VERSION 5.7 ;
  NOWIREEXTENSIONATPIN ON ;
  DIVIDERCHAR "/" ;
  BUSBITCHARS "[]" ;
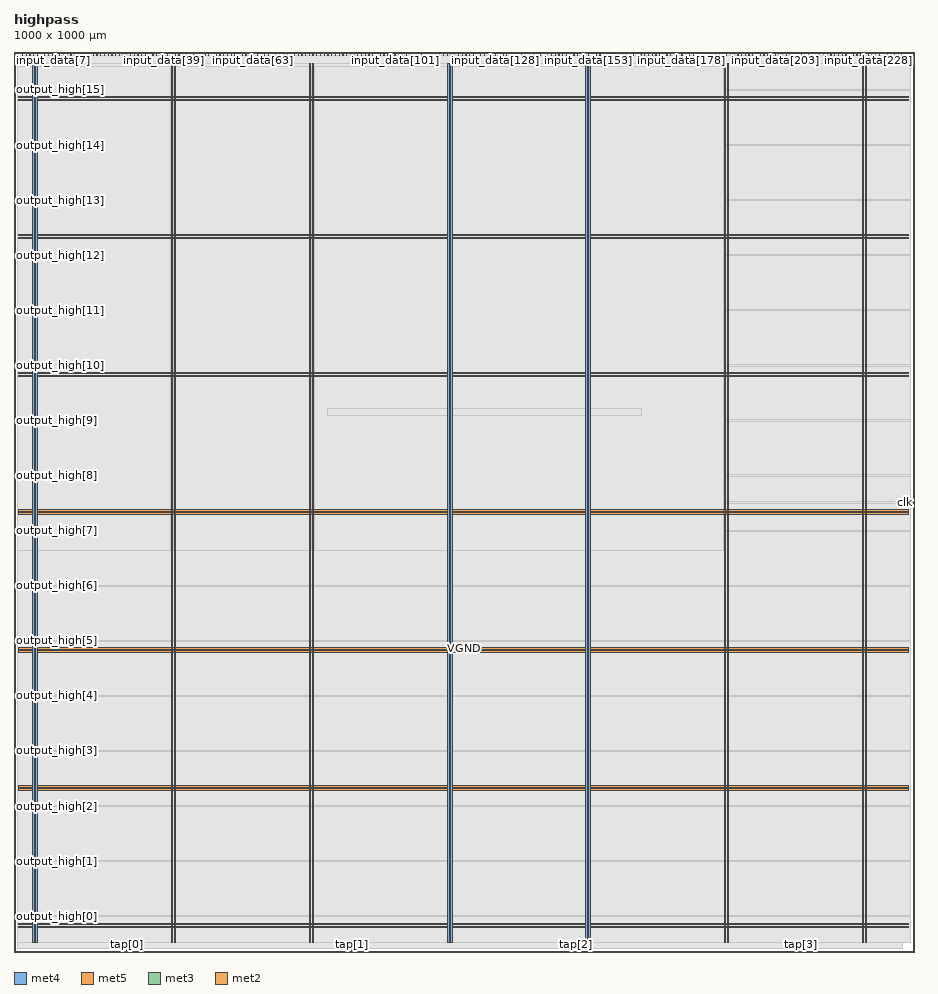
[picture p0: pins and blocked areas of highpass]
MACRO highpass
  CLASS BLOCK ;
  FOREIGN highpass ;
  ORIGIN 0.000 0.000 ;
  SIZE 1000.000 BY 1000.000 ;
  PIN VGND
    DIRECTION INOUT ;
    USE GROUND ;
    PORT
      LAYER met4 ;
        RECT 24.340 10.640 25.940 987.600 ;
    END
    PORT
      LAYER met4 ;
        RECT 177.940 10.640 179.540 987.600 ;
    END
    PORT
      LAYER met4 ;
        RECT 331.540 10.640 333.140 987.600 ;
    END
    PORT
      LAYER met4 ;
        RECT 485.140 10.640 486.740 987.600 ;
    END
    PORT
      LAYER met4 ;
        RECT 638.740 10.640 640.340 987.600 ;
    END
    PORT
      LAYER met4 ;
        RECT 792.340 10.640 793.940 987.600 ;
    END
    PORT
      LAYER met4 ;
        RECT 945.940 10.640 947.540 987.600 ;
    END
    PORT
      LAYER met5 ;
        RECT 5.280 30.030 994.300 31.630 ;
    END
    PORT
      LAYER met5 ;
        RECT 5.280 183.210 994.300 184.810 ;
    END
    PORT
      LAYER met5 ;
        RECT 5.280 336.390 994.300 337.990 ;
    END
    PORT
      LAYER met5 ;
        RECT 5.280 489.570 994.300 491.170 ;
    END
    PORT
      LAYER met5 ;
        RECT 5.280 642.750 994.300 644.350 ;
    END
    PORT
      LAYER met5 ;
        RECT 5.280 795.930 994.300 797.530 ;
    END
    PORT
      LAYER met5 ;
        RECT 5.280 949.110 994.300 950.710 ;
    END
  END VGND
  PIN VPWR
    DIRECTION INOUT ;
    USE POWER ;
    PORT
      LAYER met4 ;
        RECT 21.040 10.640 22.640 987.600 ;
    END
    PORT
      LAYER met4 ;
        RECT 174.640 10.640 176.240 987.600 ;
    END
    PORT
      LAYER met4 ;
        RECT 328.240 10.640 329.840 987.600 ;
    END
    PORT
      LAYER met4 ;
        RECT 481.840 10.640 483.440 987.600 ;
    END
    PORT
      LAYER met4 ;
        RECT 635.440 10.640 637.040 987.600 ;
    END
    PORT
      LAYER met4 ;
        RECT 789.040 10.640 790.640 987.600 ;
    END
    PORT
      LAYER met4 ;
        RECT 942.640 10.640 944.240 987.600 ;
    END
    PORT
      LAYER met5 ;
        RECT 5.280 26.730 994.300 28.330 ;
    END
    PORT
      LAYER met5 ;
        RECT 5.280 179.910 994.300 181.510 ;
    END
    PORT
      LAYER met5 ;
        RECT 5.280 333.090 994.300 334.690 ;
    END
    PORT
      LAYER met5 ;
        RECT 5.280 486.270 994.300 487.870 ;
    END
    PORT
      LAYER met5 ;
        RECT 5.280 639.450 994.300 641.050 ;
    END
    PORT
      LAYER met5 ;
        RECT 5.280 792.630 994.300 794.230 ;
    END
    PORT
      LAYER met5 ;
        RECT 5.280 945.810 994.300 947.410 ;
    END
  END VPWR
  PIN clk
    DIRECTION INPUT ;
    USE SIGNAL ;
    ANTENNAGATEAREA 0.852000 ;
    PORT
      LAYER met3 ;
        RECT 996.000 499.160 1000.000 499.760 ;
    END
  END clk
  PIN input_data[0]
    DIRECTION INPUT ;
    USE SIGNAL ;
    ANTENNAGATEAREA 0.159000 ;
    PORT
      LAYER met2 ;
        RECT 5.150 996.000 5.430 1000.000 ;
    END
  END input_data[0]
  PIN input_data[100]
    DIRECTION INPUT ;
    USE SIGNAL ;
    ANTENNAGATEAREA 0.213000 ;
    PORT
      LAYER met2 ;
        RECT 419.150 996.000 419.430 1000.000 ;
    END
  END input_data[100]
  PIN input_data[101]
    DIRECTION INPUT ;
    USE SIGNAL ;
    ANTENNAGATEAREA 0.196500 ;
    PORT
      LAYER met2 ;
        RECT 423.290 996.000 423.570 1000.000 ;
    END
  END input_data[101]
  PIN input_data[102]
    DIRECTION INPUT ;
    USE SIGNAL ;
    ANTENNAGATEAREA 0.196500 ;
    PORT
      LAYER met2 ;
        RECT 427.430 996.000 427.710 1000.000 ;
    END
  END input_data[102]
  PIN input_data[103]
    DIRECTION INPUT ;
    USE SIGNAL ;
    ANTENNAGATEAREA 0.196500 ;
    PORT
      LAYER met2 ;
        RECT 431.570 996.000 431.850 1000.000 ;
    END
  END input_data[103]
  PIN input_data[104]
    DIRECTION INPUT ;
    USE SIGNAL ;
    ANTENNAGATEAREA 0.196500 ;
    PORT
      LAYER met2 ;
        RECT 435.710 996.000 435.990 1000.000 ;
    END
  END input_data[104]
  PIN input_data[105]
    DIRECTION INPUT ;
    USE SIGNAL ;
    ANTENNAGATEAREA 0.196500 ;
    PORT
      LAYER met2 ;
        RECT 439.850 996.000 440.130 1000.000 ;
    END
  END input_data[105]
  PIN input_data[106]
    DIRECTION INPUT ;
    USE SIGNAL ;
    ANTENNAGATEAREA 0.196500 ;
    PORT
      LAYER met2 ;
        RECT 443.990 996.000 444.270 1000.000 ;
    END
  END input_data[106]
  PIN input_data[107]
    DIRECTION INPUT ;
    USE SIGNAL ;
    ANTENNAGATEAREA 0.196500 ;
    PORT
      LAYER met2 ;
        RECT 448.130 996.000 448.410 1000.000 ;
    END
  END input_data[107]
  PIN input_data[108]
    DIRECTION INPUT ;
    USE SIGNAL ;
    ANTENNAGATEAREA 0.213000 ;
    PORT
      LAYER met2 ;
        RECT 452.270 996.000 452.550 1000.000 ;
    END
  END input_data[108]
  PIN input_data[109]
    DIRECTION INPUT ;
    USE SIGNAL ;
    ANTENNAGATEAREA 0.196500 ;
    PORT
      LAYER met2 ;
        RECT 456.410 996.000 456.690 1000.000 ;
    END
  END input_data[109]
  PIN input_data[10]
    DIRECTION INPUT ;
    USE SIGNAL ;
    ANTENNAGATEAREA 0.495000 ;
    PORT
      LAYER met2 ;
        RECT 46.550 996.000 46.830 1000.000 ;
    END
  END input_data[10]
  PIN input_data[110]
    DIRECTION INPUT ;
    USE SIGNAL ;
    ANTENNAGATEAREA 0.196500 ;
    PORT
      LAYER met2 ;
        RECT 460.550 996.000 460.830 1000.000 ;
    END
  END input_data[110]
  PIN input_data[111]
    DIRECTION INPUT ;
    USE SIGNAL ;
    ANTENNAGATEAREA 0.196500 ;
    PORT
      LAYER met2 ;
        RECT 464.690 996.000 464.970 1000.000 ;
    END
  END input_data[111]
  PIN input_data[112]
    DIRECTION INPUT ;
    USE SIGNAL ;
    ANTENNAGATEAREA 0.159000 ;
    PORT
      LAYER met2 ;
        RECT 468.830 996.000 469.110 1000.000 ;
    END
  END input_data[112]
  PIN input_data[113]
    DIRECTION INPUT ;
    USE SIGNAL ;
    ANTENNAGATEAREA 0.213000 ;
    PORT
      LAYER met2 ;
        RECT 472.970 996.000 473.250 1000.000 ;
    END
  END input_data[113]
  PIN input_data[114]
    DIRECTION INPUT ;
    USE SIGNAL ;
    ANTENNAGATEAREA 0.213000 ;
    PORT
      LAYER met2 ;
        RECT 477.110 996.000 477.390 1000.000 ;
    END
  END input_data[114]
  PIN input_data[115]
    DIRECTION INPUT ;
    USE SIGNAL ;
    ANTENNAGATEAREA 0.213000 ;
    PORT
      LAYER met2 ;
        RECT 481.250 996.000 481.530 1000.000 ;
    END
  END input_data[115]
  PIN input_data[116]
    DIRECTION INPUT ;
    USE SIGNAL ;
    ANTENNAGATEAREA 0.159000 ;
    PORT
      LAYER met2 ;
        RECT 485.390 996.000 485.670 1000.000 ;
    END
  END input_data[116]
  PIN input_data[117]
    DIRECTION INPUT ;
    USE SIGNAL ;
    ANTENNAGATEAREA 0.213000 ;
    PORT
      LAYER met2 ;
        RECT 489.530 996.000 489.810 1000.000 ;
    END
  END input_data[117]
  PIN input_data[118]
    DIRECTION INPUT ;
    USE SIGNAL ;
    ANTENNAGATEAREA 0.213000 ;
    PORT
      LAYER met2 ;
        RECT 493.670 996.000 493.950 1000.000 ;
    END
  END input_data[118]
  PIN input_data[119]
    DIRECTION INPUT ;
    USE SIGNAL ;
    ANTENNAGATEAREA 0.196500 ;
    PORT
      LAYER met2 ;
        RECT 497.810 996.000 498.090 1000.000 ;
    END
  END input_data[119]
  PIN input_data[11]
    DIRECTION INPUT ;
    USE SIGNAL ;
    ANTENNAGATEAREA 0.426000 ;
    PORT
      LAYER met2 ;
        RECT 50.690 996.000 50.970 1000.000 ;
    END
  END input_data[11]
  PIN input_data[120]
    DIRECTION INPUT ;
    USE SIGNAL ;
    ANTENNAGATEAREA 0.213000 ;
    PORT
      LAYER met2 ;
        RECT 501.950 996.000 502.230 1000.000 ;
    END
  END input_data[120]
  PIN input_data[121]
    DIRECTION INPUT ;
    USE SIGNAL ;
    ANTENNAGATEAREA 0.159000 ;
    PORT
      LAYER met2 ;
        RECT 506.090 996.000 506.370 1000.000 ;
    END
  END input_data[121]
  PIN input_data[122]
    DIRECTION INPUT ;
    USE SIGNAL ;
    ANTENNAGATEAREA 0.213000 ;
    PORT
      LAYER met2 ;
        RECT 510.230 996.000 510.510 1000.000 ;
    END
  END input_data[122]
  PIN input_data[123]
    DIRECTION INPUT ;
    USE SIGNAL ;
    ANTENNAGATEAREA 0.213000 ;
    PORT
      LAYER met2 ;
        RECT 514.370 996.000 514.650 1000.000 ;
    END
  END input_data[123]
  PIN input_data[124]
    DIRECTION INPUT ;
    USE SIGNAL ;
    ANTENNAGATEAREA 0.159000 ;
    PORT
      LAYER met2 ;
        RECT 518.510 996.000 518.790 1000.000 ;
    END
  END input_data[124]
  PIN input_data[125]
    DIRECTION INPUT ;
    USE SIGNAL ;
    ANTENNAGATEAREA 0.196500 ;
    PORT
      LAYER met2 ;
        RECT 522.650 996.000 522.930 1000.000 ;
    END
  END input_data[125]
  PIN input_data[126]
    DIRECTION INPUT ;
    USE SIGNAL ;
    ANTENNAGATEAREA 0.196500 ;
    PORT
      LAYER met2 ;
        RECT 526.790 996.000 527.070 1000.000 ;
    END
  END input_data[126]
  PIN input_data[127]
    DIRECTION INPUT ;
    USE SIGNAL ;
    PORT
      LAYER met2 ;
        RECT 530.930 996.000 531.210 1000.000 ;
    END
  END input_data[127]
  PIN input_data[128]
    DIRECTION INPUT ;
    USE SIGNAL ;
    ANTENNAGATEAREA 0.159000 ;
    PORT
      LAYER met2 ;
        RECT 535.070 996.000 535.350 1000.000 ;
    END
  END input_data[128]
  PIN input_data[129]
    DIRECTION INPUT ;
    USE SIGNAL ;
    ANTENNAGATEAREA 0.159000 ;
    PORT
      LAYER met2 ;
        RECT 539.210 996.000 539.490 1000.000 ;
    END
  END input_data[129]
  PIN input_data[12]
    DIRECTION INPUT ;
    USE SIGNAL ;
    ANTENNAGATEAREA 0.742500 ;
    PORT
      LAYER met2 ;
        RECT 54.830 996.000 55.110 1000.000 ;
    END
  END input_data[12]
  PIN input_data[130]
    DIRECTION INPUT ;
    USE SIGNAL ;
    ANTENNAGATEAREA 0.213000 ;
    PORT
      LAYER met2 ;
        RECT 543.350 996.000 543.630 1000.000 ;
    END
  END input_data[130]
  PIN input_data[131]
    DIRECTION INPUT ;
    USE SIGNAL ;
    ANTENNAGATEAREA 0.213000 ;
    PORT
      LAYER met2 ;
        RECT 547.490 996.000 547.770 1000.000 ;
    END
  END input_data[131]
  PIN input_data[132]
    DIRECTION INPUT ;
    USE SIGNAL ;
    ANTENNAGATEAREA 0.213000 ;
    PORT
      LAYER met2 ;
        RECT 551.630 996.000 551.910 1000.000 ;
    END
  END input_data[132]
  PIN input_data[133]
    DIRECTION INPUT ;
    USE SIGNAL ;
    ANTENNAGATEAREA 0.426000 ;
    PORT
      LAYER met2 ;
        RECT 555.770 996.000 556.050 1000.000 ;
    END
  END input_data[133]
  PIN input_data[134]
    DIRECTION INPUT ;
    USE SIGNAL ;
    ANTENNAGATEAREA 0.247500 ;
    PORT
      LAYER met2 ;
        RECT 559.910 996.000 560.190 1000.000 ;
    END
  END input_data[134]
  PIN input_data[135]
    DIRECTION INPUT ;
    USE SIGNAL ;
    ANTENNAGATEAREA 0.426000 ;
    PORT
      LAYER met2 ;
        RECT 564.050 996.000 564.330 1000.000 ;
    END
  END input_data[135]
  PIN input_data[136]
    DIRECTION INPUT ;
    USE SIGNAL ;
    ANTENNAGATEAREA 0.852000 ;
    PORT
      LAYER met2 ;
        RECT 568.190 996.000 568.470 1000.000 ;
    END
  END input_data[136]
  PIN input_data[137]
    DIRECTION INPUT ;
    USE SIGNAL ;
    ANTENNAGATEAREA 0.742500 ;
    PORT
      LAYER met2 ;
        RECT 572.330 996.000 572.610 1000.000 ;
    END
  END input_data[137]
  PIN input_data[138]
    DIRECTION INPUT ;
    USE SIGNAL ;
    ANTENNAGATEAREA 0.426000 ;
    PORT
      LAYER met2 ;
        RECT 576.470 996.000 576.750 1000.000 ;
    END
  END input_data[138]
  PIN input_data[139]
    DIRECTION INPUT ;
    USE SIGNAL ;
    ANTENNAGATEAREA 0.495000 ;
    PORT
      LAYER met2 ;
        RECT 580.610 996.000 580.890 1000.000 ;
    END
  END input_data[139]
  PIN input_data[13]
    DIRECTION INPUT ;
    USE SIGNAL ;
    ANTENNAGATEAREA 0.742500 ;
    PORT
      LAYER met2 ;
        RECT 58.970 996.000 59.250 1000.000 ;
    END
  END input_data[13]
  PIN input_data[140]
    DIRECTION INPUT ;
    USE SIGNAL ;
    ANTENNAGATEAREA 0.426000 ;
    PORT
      LAYER met2 ;
        RECT 584.750 996.000 585.030 1000.000 ;
    END
  END input_data[140]
  PIN input_data[141]
    DIRECTION INPUT ;
    USE SIGNAL ;
    ANTENNAGATEAREA 0.426000 ;
    PORT
      LAYER met2 ;
        RECT 588.890 996.000 589.170 1000.000 ;
    END
  END input_data[141]
  PIN input_data[142]
    DIRECTION INPUT ;
    USE SIGNAL ;
    ANTENNAGATEAREA 0.213000 ;
    PORT
      LAYER met2 ;
        RECT 593.030 996.000 593.310 1000.000 ;
    END
  END input_data[142]
  PIN input_data[143]
    DIRECTION INPUT ;
    USE SIGNAL ;
    ANTENNAGATEAREA 0.159000 ;
    PORT
      LAYER met2 ;
        RECT 597.170 996.000 597.450 1000.000 ;
    END
  END input_data[143]
  PIN input_data[144]
    DIRECTION INPUT ;
    USE SIGNAL ;
    ANTENNAGATEAREA 0.213000 ;
    PORT
      LAYER met2 ;
        RECT 601.310 996.000 601.590 1000.000 ;
    END
  END input_data[144]
  PIN input_data[145]
    DIRECTION INPUT ;
    USE SIGNAL ;
    ANTENNAGATEAREA 0.159000 ;
    PORT
      LAYER met2 ;
        RECT 605.450 996.000 605.730 1000.000 ;
    END
  END input_data[145]
  PIN input_data[146]
    DIRECTION INPUT ;
    USE SIGNAL ;
    ANTENNAGATEAREA 0.159000 ;
    PORT
      LAYER met2 ;
        RECT 609.590 996.000 609.870 1000.000 ;
    END
  END input_data[146]
  PIN input_data[147]
    DIRECTION INPUT ;
    USE SIGNAL ;
    ANTENNAGATEAREA 0.159000 ;
    PORT
      LAYER met2 ;
        RECT 613.730 996.000 614.010 1000.000 ;
    END
  END input_data[147]
  PIN input_data[148]
    DIRECTION INPUT ;
    USE SIGNAL ;
    ANTENNAGATEAREA 0.159000 ;
    PORT
      LAYER met2 ;
        RECT 617.870 996.000 618.150 1000.000 ;
    END
  END input_data[148]
  PIN input_data[149]
    DIRECTION INPUT ;
    USE SIGNAL ;
    ANTENNAGATEAREA 0.213000 ;
    PORT
      LAYER met2 ;
        RECT 622.010 996.000 622.290 1000.000 ;
    END
  END input_data[149]
  PIN input_data[14]
    DIRECTION INPUT ;
    USE SIGNAL ;
    ANTENNAGATEAREA 0.213000 ;
    PORT
      LAYER met2 ;
        RECT 63.110 996.000 63.390 1000.000 ;
    END
  END input_data[14]
  PIN input_data[150]
    DIRECTION INPUT ;
    USE SIGNAL ;
    ANTENNAGATEAREA 0.159000 ;
    PORT
      LAYER met2 ;
        RECT 626.150 996.000 626.430 1000.000 ;
    END
  END input_data[150]
  PIN input_data[151]
    DIRECTION INPUT ;
    USE SIGNAL ;
    ANTENNAGATEAREA 0.213000 ;
    PORT
      LAYER met2 ;
        RECT 630.290 996.000 630.570 1000.000 ;
    END
  END input_data[151]
  PIN input_data[152]
    DIRECTION INPUT ;
    USE SIGNAL ;
    ANTENNAGATEAREA 0.213000 ;
    PORT
      LAYER met2 ;
        RECT 634.430 996.000 634.710 1000.000 ;
    END
  END input_data[152]
  PIN input_data[153]
    DIRECTION INPUT ;
    USE SIGNAL ;
    ANTENNAGATEAREA 0.159000 ;
    PORT
      LAYER met2 ;
        RECT 638.570 996.000 638.850 1000.000 ;
    END
  END input_data[153]
  PIN input_data[154]
    DIRECTION INPUT ;
    USE SIGNAL ;
    ANTENNAGATEAREA 0.159000 ;
    PORT
      LAYER met2 ;
        RECT 642.710 996.000 642.990 1000.000 ;
    END
  END input_data[154]
  PIN input_data[155]
    DIRECTION INPUT ;
    USE SIGNAL ;
    ANTENNAGATEAREA 0.159000 ;
    PORT
      LAYER met2 ;
        RECT 646.850 996.000 647.130 1000.000 ;
    END
  END input_data[155]
  PIN input_data[156]
    DIRECTION INPUT ;
    USE SIGNAL ;
    ANTENNAGATEAREA 0.742500 ;
    PORT
      LAYER met2 ;
        RECT 650.990 996.000 651.270 1000.000 ;
    END
  END input_data[156]
  PIN input_data[157]
    DIRECTION INPUT ;
    USE SIGNAL ;
    ANTENNAGATEAREA 0.247500 ;
    PORT
      LAYER met2 ;
        RECT 655.130 996.000 655.410 1000.000 ;
    END
  END input_data[157]
  PIN input_data[158]
    DIRECTION INPUT ;
    USE SIGNAL ;
    ANTENNAGATEAREA 0.196500 ;
    PORT
      LAYER met2 ;
        RECT 659.270 996.000 659.550 1000.000 ;
    END
  END input_data[158]
  PIN input_data[159]
    DIRECTION INPUT ;
    USE SIGNAL ;
    ANTENNAGATEAREA 0.213000 ;
    PORT
      LAYER met2 ;
        RECT 663.410 996.000 663.690 1000.000 ;
    END
  END input_data[159]
  PIN input_data[15]
    DIRECTION INPUT ;
    USE SIGNAL ;
    ANTENNAGATEAREA 0.213000 ;
    PORT
      LAYER met2 ;
        RECT 67.250 996.000 67.530 1000.000 ;
    END
  END input_data[15]
  PIN input_data[160]
    DIRECTION INPUT ;
    USE SIGNAL ;
    ANTENNAGATEAREA 0.495000 ;
    PORT
      LAYER met2 ;
        RECT 667.550 996.000 667.830 1000.000 ;
    END
  END input_data[160]
  PIN input_data[161]
    DIRECTION INPUT ;
    USE SIGNAL ;
    ANTENNAGATEAREA 0.742500 ;
    PORT
      LAYER met2 ;
        RECT 671.690 996.000 671.970 1000.000 ;
    END
  END input_data[161]
  PIN input_data[162]
    DIRECTION INPUT ;
    USE SIGNAL ;
    ANTENNAGATEAREA 0.426000 ;
    PORT
      LAYER met2 ;
        RECT 675.830 996.000 676.110 1000.000 ;
    END
  END input_data[162]
  PIN input_data[163]
    DIRECTION INPUT ;
    USE SIGNAL ;
    ANTENNAGATEAREA 0.426000 ;
    PORT
      LAYER met2 ;
        RECT 679.970 996.000 680.250 1000.000 ;
    END
  END input_data[163]
  PIN input_data[164]
    DIRECTION INPUT ;
    USE SIGNAL ;
    ANTENNAGATEAREA 0.213000 ;
    PORT
      LAYER met2 ;
        RECT 684.110 996.000 684.390 1000.000 ;
    END
  END input_data[164]
  PIN input_data[165]
    DIRECTION INPUT ;
    USE SIGNAL ;
    ANTENNAGATEAREA 0.213000 ;
    PORT
      LAYER met2 ;
        RECT 688.250 996.000 688.530 1000.000 ;
    END
  END input_data[165]
  PIN input_data[166]
    DIRECTION INPUT ;
    USE SIGNAL ;
    ANTENNAGATEAREA 0.213000 ;
    PORT
      LAYER met2 ;
        RECT 692.390 996.000 692.670 1000.000 ;
    END
  END input_data[166]
  PIN input_data[167]
    DIRECTION INPUT ;
    USE SIGNAL ;
    ANTENNAGATEAREA 0.159000 ;
    PORT
      LAYER met2 ;
        RECT 696.530 996.000 696.810 1000.000 ;
    END
  END input_data[167]
  PIN input_data[168]
    DIRECTION INPUT ;
    USE SIGNAL ;
    ANTENNAGATEAREA 0.159000 ;
    PORT
      LAYER met2 ;
        RECT 700.670 996.000 700.950 1000.000 ;
    END
  END input_data[168]
  PIN input_data[169]
    DIRECTION INPUT ;
    USE SIGNAL ;
    ANTENNAGATEAREA 0.213000 ;
    PORT
      LAYER met2 ;
        RECT 704.810 996.000 705.090 1000.000 ;
    END
  END input_data[169]
  PIN input_data[16]
    DIRECTION INPUT ;
    USE SIGNAL ;
    ANTENNAGATEAREA 0.247500 ;
    PORT
      LAYER met2 ;
        RECT 71.390 996.000 71.670 1000.000 ;
    END
  END input_data[16]
  PIN input_data[170]
    DIRECTION INPUT ;
    USE SIGNAL ;
    ANTENNAGATEAREA 0.126000 ;
    PORT
      LAYER met2 ;
        RECT 708.950 996.000 709.230 1000.000 ;
    END
  END input_data[170]
  PIN input_data[171]
    DIRECTION INPUT ;
    USE SIGNAL ;
    ANTENNAGATEAREA 0.426000 ;
    PORT
      LAYER met2 ;
        RECT 713.090 996.000 713.370 1000.000 ;
    END
  END input_data[171]
  PIN input_data[172]
    DIRECTION INPUT ;
    USE SIGNAL ;
    ANTENNAGATEAREA 0.247500 ;
    PORT
      LAYER met2 ;
        RECT 717.230 996.000 717.510 1000.000 ;
    END
  END input_data[172]
  PIN input_data[173]
    DIRECTION INPUT ;
    USE SIGNAL ;
    ANTENNAGATEAREA 0.426000 ;
    PORT
      LAYER met2 ;
        RECT 721.370 996.000 721.650 1000.000 ;
    END
  END input_data[173]
  PIN input_data[174]
    DIRECTION INPUT ;
    USE SIGNAL ;
    ANTENNAGATEAREA 0.196500 ;
    PORT
      LAYER met2 ;
        RECT 725.510 996.000 725.790 1000.000 ;
    END
  END input_data[174]
  PIN input_data[175]
    DIRECTION INPUT ;
    USE SIGNAL ;
    ANTENNAGATEAREA 0.196500 ;
    PORT
      LAYER met2 ;
        RECT 729.650 996.000 729.930 1000.000 ;
    END
  END input_data[175]
  PIN input_data[176]
    DIRECTION INPUT ;
    USE SIGNAL ;
    ANTENNAGATEAREA 0.213000 ;
    PORT
      LAYER met2 ;
        RECT 733.790 996.000 734.070 1000.000 ;
    END
  END input_data[176]
  PIN input_data[177]
    DIRECTION INPUT ;
    USE SIGNAL ;
    ANTENNAGATEAREA 0.247500 ;
    PORT
      LAYER met2 ;
        RECT 737.930 996.000 738.210 1000.000 ;
    END
  END input_data[177]
  PIN input_data[178]
    DIRECTION INPUT ;
    USE SIGNAL ;
    ANTENNAGATEAREA 0.247500 ;
    PORT
      LAYER met2 ;
        RECT 742.070 996.000 742.350 1000.000 ;
    END
  END input_data[178]
  PIN input_data[179]
    DIRECTION INPUT ;
    USE SIGNAL ;
    ANTENNAGATEAREA 0.426000 ;
    PORT
      LAYER met2 ;
        RECT 746.210 996.000 746.490 1000.000 ;
    END
  END input_data[179]
  PIN input_data[17]
    DIRECTION INPUT ;
    USE SIGNAL ;
    ANTENNAGATEAREA 0.742500 ;
    PORT
      LAYER met2 ;
        RECT 75.530 996.000 75.810 1000.000 ;
    END
  END input_data[17]
  PIN input_data[180]
    DIRECTION INPUT ;
    USE SIGNAL ;
    ANTENNAGATEAREA 0.495000 ;
    PORT
      LAYER met2 ;
        RECT 750.350 996.000 750.630 1000.000 ;
    END
  END input_data[180]
  PIN input_data[181]
    DIRECTION INPUT ;
    USE SIGNAL ;
    ANTENNAGATEAREA 0.247500 ;
    PORT
      LAYER met2 ;
        RECT 754.490 996.000 754.770 1000.000 ;
    END
  END input_data[181]
  PIN input_data[182]
    DIRECTION INPUT ;
    USE SIGNAL ;
    ANTENNAGATEAREA 0.213000 ;
    PORT
      LAYER met2 ;
        RECT 758.630 996.000 758.910 1000.000 ;
    END
  END input_data[182]
  PIN input_data[183]
    DIRECTION INPUT ;
    USE SIGNAL ;
    ANTENNAGATEAREA 0.213000 ;
    PORT
      LAYER met2 ;
        RECT 762.770 996.000 763.050 1000.000 ;
    END
  END input_data[183]
  PIN input_data[184]
    DIRECTION INPUT ;
    USE SIGNAL ;
    ANTENNAGATEAREA 0.213000 ;
    PORT
      LAYER met2 ;
        RECT 766.910 996.000 767.190 1000.000 ;
    END
  END input_data[184]
  PIN input_data[185]
    DIRECTION INPUT ;
    USE SIGNAL ;
    ANTENNAGATEAREA 0.213000 ;
    PORT
      LAYER met2 ;
        RECT 771.050 996.000 771.330 1000.000 ;
    END
  END input_data[185]
  PIN input_data[186]
    DIRECTION INPUT ;
    USE SIGNAL ;
    ANTENNAGATEAREA 0.247500 ;
    PORT
      LAYER met2 ;
        RECT 775.190 996.000 775.470 1000.000 ;
    END
  END input_data[186]
  PIN input_data[187]
    DIRECTION INPUT ;
    USE SIGNAL ;
    ANTENNAGATEAREA 0.159000 ;
    PORT
      LAYER met2 ;
        RECT 779.330 996.000 779.610 1000.000 ;
    END
  END input_data[187]
  PIN input_data[188]
    DIRECTION INPUT ;
    USE SIGNAL ;
    ANTENNAGATEAREA 0.247500 ;
    PORT
      LAYER met2 ;
        RECT 783.470 996.000 783.750 1000.000 ;
    END
  END input_data[188]
  PIN input_data[189]
    DIRECTION INPUT ;
    USE SIGNAL ;
    ANTENNAGATEAREA 0.196500 ;
    PORT
      LAYER met2 ;
        RECT 787.610 996.000 787.890 1000.000 ;
    END
  END input_data[189]
  PIN input_data[18]
    DIRECTION INPUT ;
    USE SIGNAL ;
    ANTENNAGATEAREA 0.742500 ;
    PORT
      LAYER met2 ;
        RECT 79.670 996.000 79.950 1000.000 ;
    END
  END input_data[18]
  PIN input_data[190]
    DIRECTION INPUT ;
    USE SIGNAL ;
    ANTENNAGATEAREA 0.196500 ;
    PORT
      LAYER met2 ;
        RECT 791.750 996.000 792.030 1000.000 ;
    END
  END input_data[190]
  PIN input_data[191]
    DIRECTION INPUT ;
    USE SIGNAL ;
    PORT
      LAYER met2 ;
        RECT 795.890 996.000 796.170 1000.000 ;
    END
  END input_data[191]
  PIN input_data[192]
    DIRECTION INPUT ;
    USE SIGNAL ;
    ANTENNAGATEAREA 0.213000 ;
    PORT
      LAYER met2 ;
        RECT 800.030 996.000 800.310 1000.000 ;
    END
  END input_data[192]
  PIN input_data[193]
    DIRECTION INPUT ;
    USE SIGNAL ;
    ANTENNAGATEAREA 0.159000 ;
    PORT
      LAYER met2 ;
        RECT 804.170 996.000 804.450 1000.000 ;
    END
  END input_data[193]
  PIN input_data[194]
    DIRECTION INPUT ;
    USE SIGNAL ;
    ANTENNAGATEAREA 0.213000 ;
    PORT
      LAYER met2 ;
        RECT 808.310 996.000 808.590 1000.000 ;
    END
  END input_data[194]
  PIN input_data[195]
    DIRECTION INPUT ;
    USE SIGNAL ;
    ANTENNAGATEAREA 0.213000 ;
    PORT
      LAYER met2 ;
        RECT 812.450 996.000 812.730 1000.000 ;
    END
  END input_data[195]
  PIN input_data[196]
    DIRECTION INPUT ;
    USE SIGNAL ;
    ANTENNAGATEAREA 0.213000 ;
    PORT
      LAYER met2 ;
        RECT 816.590 996.000 816.870 1000.000 ;
    END
  END input_data[196]
  PIN input_data[197]
    DIRECTION INPUT ;
    USE SIGNAL ;
    ANTENNAGATEAREA 0.213000 ;
    PORT
      LAYER met2 ;
        RECT 820.730 996.000 821.010 1000.000 ;
    END
  END input_data[197]
  PIN input_data[198]
    DIRECTION INPUT ;
    USE SIGNAL ;
    ANTENNAGATEAREA 0.213000 ;
    PORT
      LAYER met2 ;
        RECT 824.870 996.000 825.150 1000.000 ;
    END
  END input_data[198]
  PIN input_data[199]
    DIRECTION INPUT ;
    USE SIGNAL ;
    ANTENNAGATEAREA 0.213000 ;
    PORT
      LAYER met2 ;
        RECT 829.010 996.000 829.290 1000.000 ;
    END
  END input_data[199]
  PIN input_data[19]
    DIRECTION INPUT ;
    USE SIGNAL ;
    ANTENNAGATEAREA 0.247500 ;
    PORT
      LAYER met2 ;
        RECT 83.810 996.000 84.090 1000.000 ;
    END
  END input_data[19]
  PIN input_data[1]
    DIRECTION INPUT ;
    USE SIGNAL ;
    ANTENNAGATEAREA 0.213000 ;
    PORT
      LAYER met2 ;
        RECT 9.290 996.000 9.570 1000.000 ;
    END
  END input_data[1]
  PIN input_data[200]
    DIRECTION INPUT ;
    USE SIGNAL ;
    ANTENNAGATEAREA 0.213000 ;
    PORT
      LAYER met2 ;
        RECT 833.150 996.000 833.430 1000.000 ;
    END
  END input_data[200]
  PIN input_data[201]
    DIRECTION INPUT ;
    USE SIGNAL ;
    ANTENNAGATEAREA 0.213000 ;
    PORT
      LAYER met2 ;
        RECT 837.290 996.000 837.570 1000.000 ;
    END
  END input_data[201]
  PIN input_data[202]
    DIRECTION INPUT ;
    USE SIGNAL ;
    ANTENNAGATEAREA 0.213000 ;
    PORT
      LAYER met2 ;
        RECT 841.430 996.000 841.710 1000.000 ;
    END
  END input_data[202]
  PIN input_data[203]
    DIRECTION INPUT ;
    USE SIGNAL ;
    ANTENNAGATEAREA 0.126000 ;
    PORT
      LAYER met2 ;
        RECT 845.570 996.000 845.850 1000.000 ;
    END
  END input_data[203]
  PIN input_data[204]
    DIRECTION INPUT ;
    USE SIGNAL ;
    ANTENNAGATEAREA 0.196500 ;
    PORT
      LAYER met2 ;
        RECT 849.710 996.000 849.990 1000.000 ;
    END
  END input_data[204]
  PIN input_data[205]
    DIRECTION INPUT ;
    USE SIGNAL ;
    ANTENNAGATEAREA 0.196500 ;
    PORT
      LAYER met2 ;
        RECT 853.850 996.000 854.130 1000.000 ;
    END
  END input_data[205]
  PIN input_data[206]
    DIRECTION INPUT ;
    USE SIGNAL ;
    ANTENNAGATEAREA 0.196500 ;
    PORT
      LAYER met2 ;
        RECT 857.990 996.000 858.270 1000.000 ;
    END
  END input_data[206]
  PIN input_data[207]
    DIRECTION INPUT ;
    USE SIGNAL ;
    PORT
      LAYER met2 ;
        RECT 862.130 996.000 862.410 1000.000 ;
    END
  END input_data[207]
  PIN input_data[208]
    DIRECTION INPUT ;
    USE SIGNAL ;
    PORT
      LAYER met2 ;
        RECT 866.270 996.000 866.550 1000.000 ;
    END
  END input_data[208]
  PIN input_data[209]
    DIRECTION INPUT ;
    USE SIGNAL ;
    PORT
      LAYER met2 ;
        RECT 870.410 996.000 870.690 1000.000 ;
    END
  END input_data[209]
  PIN input_data[20]
    DIRECTION INPUT ;
    USE SIGNAL ;
    ANTENNAGATEAREA 0.426000 ;
    PORT
      LAYER met2 ;
        RECT 87.950 996.000 88.230 1000.000 ;
    END
  END input_data[20]
  PIN input_data[210]
    DIRECTION INPUT ;
    USE SIGNAL ;
    PORT
      LAYER met2 ;
        RECT 874.550 996.000 874.830 1000.000 ;
    END
  END input_data[210]
  PIN input_data[211]
    DIRECTION INPUT ;
    USE SIGNAL ;
    PORT
      LAYER met2 ;
        RECT 878.690 996.000 878.970 1000.000 ;
    END
  END input_data[211]
  PIN input_data[212]
    DIRECTION INPUT ;
    USE SIGNAL ;
    PORT
      LAYER met2 ;
        RECT 882.830 996.000 883.110 1000.000 ;
    END
  END input_data[212]
  PIN input_data[213]
    DIRECTION INPUT ;
    USE SIGNAL ;
    PORT
      LAYER met2 ;
        RECT 886.970 996.000 887.250 1000.000 ;
    END
  END input_data[213]
  PIN input_data[214]
    DIRECTION INPUT ;
    USE SIGNAL ;
    PORT
      LAYER met2 ;
        RECT 891.110 996.000 891.390 1000.000 ;
    END
  END input_data[214]
  PIN input_data[215]
    DIRECTION INPUT ;
    USE SIGNAL ;
    PORT
      LAYER met2 ;
        RECT 895.250 996.000 895.530 1000.000 ;
    END
  END input_data[215]
  PIN input_data[216]
    DIRECTION INPUT ;
    USE SIGNAL ;
    PORT
      LAYER met2 ;
        RECT 899.390 996.000 899.670 1000.000 ;
    END
  END input_data[216]
  PIN input_data[217]
    DIRECTION INPUT ;
    USE SIGNAL ;
    PORT
      LAYER met2 ;
        RECT 903.530 996.000 903.810 1000.000 ;
    END
  END input_data[217]
  PIN input_data[218]
    DIRECTION INPUT ;
    USE SIGNAL ;
    PORT
      LAYER met2 ;
        RECT 907.670 996.000 907.950 1000.000 ;
    END
  END input_data[218]
  PIN input_data[219]
    DIRECTION INPUT ;
    USE SIGNAL ;
    PORT
      LAYER met2 ;
        RECT 911.810 996.000 912.090 1000.000 ;
    END
  END input_data[219]
  PIN input_data[21]
    DIRECTION INPUT ;
    USE SIGNAL ;
    ANTENNAGATEAREA 0.495000 ;
    PORT
      LAYER met2 ;
        RECT 92.090 996.000 92.370 1000.000 ;
    END
  END input_data[21]
  PIN input_data[220]
    DIRECTION INPUT ;
    USE SIGNAL ;
    PORT
      LAYER met2 ;
        RECT 915.950 996.000 916.230 1000.000 ;
    END
  END input_data[220]
  PIN input_data[221]
    DIRECTION INPUT ;
    USE SIGNAL ;
    PORT
      LAYER met2 ;
        RECT 920.090 996.000 920.370 1000.000 ;
    END
  END input_data[221]
  PIN input_data[222]
    DIRECTION INPUT ;
    USE SIGNAL ;
    PORT
      LAYER met2 ;
        RECT 924.230 996.000 924.510 1000.000 ;
    END
  END input_data[222]
  PIN input_data[223]
    DIRECTION INPUT ;
    USE SIGNAL ;
    PORT
      LAYER met2 ;
        RECT 928.370 996.000 928.650 1000.000 ;
    END
  END input_data[223]
  PIN input_data[224]
    DIRECTION INPUT ;
    USE SIGNAL ;
    ANTENNAGATEAREA 0.247500 ;
    PORT
      LAYER met2 ;
        RECT 932.510 996.000 932.790 1000.000 ;
    END
  END input_data[224]
  PIN input_data[225]
    DIRECTION INPUT ;
    USE SIGNAL ;
    ANTENNAGATEAREA 0.247500 ;
    PORT
      LAYER met2 ;
        RECT 936.650 996.000 936.930 1000.000 ;
    END
  END input_data[225]
  PIN input_data[226]
    DIRECTION INPUT ;
    USE SIGNAL ;
    ANTENNAGATEAREA 0.426000 ;
    PORT
      LAYER met2 ;
        RECT 940.790 996.000 941.070 1000.000 ;
    END
  END input_data[226]
  PIN input_data[227]
    DIRECTION INPUT ;
    USE SIGNAL ;
    ANTENNAGATEAREA 0.247500 ;
    PORT
      LAYER met2 ;
        RECT 944.930 996.000 945.210 1000.000 ;
    END
  END input_data[227]
  PIN input_data[228]
    DIRECTION INPUT ;
    USE SIGNAL ;
    ANTENNAGATEAREA 0.159000 ;
    PORT
      LAYER met2 ;
        RECT 949.070 996.000 949.350 1000.000 ;
    END
  END input_data[228]
  PIN input_data[229]
    DIRECTION INPUT ;
    USE SIGNAL ;
    ANTENNAGATEAREA 0.159000 ;
    PORT
      LAYER met2 ;
        RECT 953.210 996.000 953.490 1000.000 ;
    END
  END input_data[229]
  PIN input_data[22]
    DIRECTION INPUT ;
    USE SIGNAL ;
    ANTENNAGATEAREA 0.742500 ;
    PORT
      LAYER met2 ;
        RECT 96.230 996.000 96.510 1000.000 ;
    END
  END input_data[22]
  PIN input_data[230]
    DIRECTION INPUT ;
    USE SIGNAL ;
    ANTENNAGATEAREA 0.213000 ;
    PORT
      LAYER met2 ;
        RECT 957.350 996.000 957.630 1000.000 ;
    END
  END input_data[230]
  PIN input_data[231]
    DIRECTION INPUT ;
    USE SIGNAL ;
    ANTENNAGATEAREA 0.159000 ;
    PORT
      LAYER met2 ;
        RECT 961.490 996.000 961.770 1000.000 ;
    END
  END input_data[231]
  PIN input_data[232]
    DIRECTION INPUT ;
    USE SIGNAL ;
    ANTENNAGATEAREA 0.213000 ;
    PORT
      LAYER met2 ;
        RECT 965.630 996.000 965.910 1000.000 ;
    END
  END input_data[232]
  PIN input_data[233]
    DIRECTION INPUT ;
    USE SIGNAL ;
    ANTENNAGATEAREA 0.213000 ;
    PORT
      LAYER met2 ;
        RECT 969.770 996.000 970.050 1000.000 ;
    END
  END input_data[233]
  PIN input_data[234]
    DIRECTION INPUT ;
    USE SIGNAL ;
    ANTENNAGATEAREA 0.126000 ;
    PORT
      LAYER met2 ;
        RECT 973.910 996.000 974.190 1000.000 ;
    END
  END input_data[234]
  PIN input_data[235]
    DIRECTION INPUT ;
    USE SIGNAL ;
    ANTENNAGATEAREA 0.196500 ;
    PORT
      LAYER met2 ;
        RECT 978.050 996.000 978.330 1000.000 ;
    END
  END input_data[235]
  PIN input_data[236]
    DIRECTION INPUT ;
    USE SIGNAL ;
    ANTENNAGATEAREA 0.196500 ;
    PORT
      LAYER met2 ;
        RECT 982.190 996.000 982.470 1000.000 ;
    END
  END input_data[236]
  PIN input_data[237]
    DIRECTION INPUT ;
    USE SIGNAL ;
    ANTENNAGATEAREA 0.196500 ;
    PORT
      LAYER met2 ;
        RECT 986.330 996.000 986.610 1000.000 ;
    END
  END input_data[237]
  PIN input_data[238]
    DIRECTION INPUT ;
    USE SIGNAL ;
    PORT
      LAYER met2 ;
        RECT 990.470 996.000 990.750 1000.000 ;
    END
  END input_data[238]
  PIN input_data[239]
    DIRECTION INPUT ;
    USE SIGNAL ;
    PORT
      LAYER met2 ;
        RECT 994.610 996.000 994.890 1000.000 ;
    END
  END input_data[239]
  PIN input_data[23]
    DIRECTION INPUT ;
    USE SIGNAL ;
    ANTENNAGATEAREA 0.742500 ;
    PORT
      LAYER met2 ;
        RECT 100.370 996.000 100.650 1000.000 ;
    END
  END input_data[23]
  PIN input_data[24]
    DIRECTION INPUT ;
    USE SIGNAL ;
    ANTENNAGATEAREA 0.742500 ;
    PORT
      LAYER met2 ;
        RECT 104.510 996.000 104.790 1000.000 ;
    END
  END input_data[24]
  PIN input_data[25]
    DIRECTION INPUT ;
    USE SIGNAL ;
    ANTENNAGATEAREA 0.247500 ;
    PORT
      LAYER met2 ;
        RECT 108.650 996.000 108.930 1000.000 ;
    END
  END input_data[25]
  PIN input_data[26]
    DIRECTION INPUT ;
    USE SIGNAL ;
    ANTENNAGATEAREA 0.495000 ;
    PORT
      LAYER met2 ;
        RECT 112.790 996.000 113.070 1000.000 ;
    END
  END input_data[26]
  PIN input_data[27]
    DIRECTION INPUT ;
    USE SIGNAL ;
    ANTENNAGATEAREA 0.742500 ;
    PORT
      LAYER met2 ;
        RECT 116.930 996.000 117.210 1000.000 ;
    END
  END input_data[27]
  PIN input_data[28]
    DIRECTION INPUT ;
    USE SIGNAL ;
    ANTENNAGATEAREA 0.196500 ;
    PORT
      LAYER met2 ;
        RECT 121.070 996.000 121.350 1000.000 ;
    END
  END input_data[28]
  PIN input_data[29]
    DIRECTION INPUT ;
    USE SIGNAL ;
    ANTENNAGATEAREA 0.426000 ;
    PORT
      LAYER met2 ;
        RECT 125.210 996.000 125.490 1000.000 ;
    END
  END input_data[29]
  PIN input_data[2]
    DIRECTION INPUT ;
    USE SIGNAL ;
    ANTENNAGATEAREA 0.213000 ;
    PORT
      LAYER met2 ;
        RECT 13.430 996.000 13.710 1000.000 ;
    END
  END input_data[2]
  PIN input_data[30]
    DIRECTION INPUT ;
    USE SIGNAL ;
    ANTENNAGATEAREA 0.247500 ;
    PORT
      LAYER met2 ;
        RECT 129.350 996.000 129.630 1000.000 ;
    END
  END input_data[30]
  PIN input_data[31]
    DIRECTION INPUT ;
    USE SIGNAL ;
    ANTENNAGATEAREA 0.126000 ;
    PORT
      LAYER met2 ;
        RECT 133.490 996.000 133.770 1000.000 ;
    END
  END input_data[31]
  PIN input_data[32]
    DIRECTION INPUT ;
    USE SIGNAL ;
    ANTENNAGATEAREA 0.159000 ;
    PORT
      LAYER met2 ;
        RECT 137.630 996.000 137.910 1000.000 ;
    END
  END input_data[32]
  PIN input_data[33]
    DIRECTION INPUT ;
    USE SIGNAL ;
    ANTENNAGATEAREA 0.426000 ;
    PORT
      LAYER met2 ;
        RECT 141.770 996.000 142.050 1000.000 ;
    END
  END input_data[33]
  PIN input_data[34]
    DIRECTION INPUT ;
    USE SIGNAL ;
    ANTENNAGATEAREA 0.213000 ;
    PORT
      LAYER met2 ;
        RECT 145.910 996.000 146.190 1000.000 ;
    END
  END input_data[34]
  PIN input_data[35]
    DIRECTION INPUT ;
    USE SIGNAL ;
    ANTENNAGATEAREA 0.213000 ;
    PORT
      LAYER met2 ;
        RECT 150.050 996.000 150.330 1000.000 ;
    END
  END input_data[35]
  PIN input_data[36]
    DIRECTION INPUT ;
    USE SIGNAL ;
    ANTENNAGATEAREA 0.213000 ;
    PORT
      LAYER met2 ;
        RECT 154.190 996.000 154.470 1000.000 ;
    END
  END input_data[36]
  PIN input_data[37]
    DIRECTION INPUT ;
    USE SIGNAL ;
    ANTENNAGATEAREA 0.213000 ;
    PORT
      LAYER met2 ;
        RECT 158.330 996.000 158.610 1000.000 ;
    END
  END input_data[37]
  PIN input_data[38]
    DIRECTION INPUT ;
    USE SIGNAL ;
    ANTENNAGATEAREA 0.213000 ;
    PORT
      LAYER met2 ;
        RECT 162.470 996.000 162.750 1000.000 ;
    END
  END input_data[38]
  PIN input_data[39]
    DIRECTION INPUT ;
    USE SIGNAL ;
    ANTENNAGATEAREA 0.213000 ;
    PORT
      LAYER met2 ;
        RECT 166.610 996.000 166.890 1000.000 ;
    END
  END input_data[39]
  PIN input_data[3]
    DIRECTION INPUT ;
    USE SIGNAL ;
    ANTENNAGATEAREA 0.213000 ;
    PORT
      LAYER met2 ;
        RECT 17.570 996.000 17.850 1000.000 ;
    END
  END input_data[3]
  PIN input_data[40]
    DIRECTION INPUT ;
    USE SIGNAL ;
    ANTENNAGATEAREA 0.247500 ;
    PORT
      LAYER met2 ;
        RECT 170.750 996.000 171.030 1000.000 ;
    END
  END input_data[40]
  PIN input_data[41]
    DIRECTION INPUT ;
    USE SIGNAL ;
    ANTENNAGATEAREA 0.159000 ;
    PORT
      LAYER met2 ;
        RECT 174.890 996.000 175.170 1000.000 ;
    END
  END input_data[41]
  PIN input_data[42]
    DIRECTION INPUT ;
    USE SIGNAL ;
    ANTENNAGATEAREA 0.159000 ;
    PORT
      LAYER met2 ;
        RECT 179.030 996.000 179.310 1000.000 ;
    END
  END input_data[42]
  PIN input_data[43]
    DIRECTION INPUT ;
    USE SIGNAL ;
    ANTENNAGATEAREA 0.213000 ;
    PORT
      LAYER met2 ;
        RECT 183.170 996.000 183.450 1000.000 ;
    END
  END input_data[43]
  PIN input_data[44]
    DIRECTION INPUT ;
    USE SIGNAL ;
    ANTENNAGATEAREA 0.426000 ;
    PORT
      LAYER met2 ;
        RECT 187.310 996.000 187.590 1000.000 ;
    END
  END input_data[44]
  PIN input_data[45]
    DIRECTION INPUT ;
    USE SIGNAL ;
    ANTENNAGATEAREA 0.426000 ;
    PORT
      LAYER met2 ;
        RECT 191.450 996.000 191.730 1000.000 ;
    END
  END input_data[45]
  PIN input_data[46]
    DIRECTION INPUT ;
    USE SIGNAL ;
    ANTENNAGATEAREA 0.159000 ;
    PORT
      LAYER met2 ;
        RECT 195.590 996.000 195.870 1000.000 ;
    END
  END input_data[46]
  PIN input_data[47]
    DIRECTION INPUT ;
    USE SIGNAL ;
    ANTENNAGATEAREA 0.126000 ;
    PORT
      LAYER met2 ;
        RECT 199.730 996.000 200.010 1000.000 ;
    END
  END input_data[47]
  PIN input_data[48]
    DIRECTION INPUT ;
    USE SIGNAL ;
    ANTENNAGATEAREA 0.159000 ;
    PORT
      LAYER met2 ;
        RECT 203.870 996.000 204.150 1000.000 ;
    END
  END input_data[48]
  PIN input_data[49]
    DIRECTION INPUT ;
    USE SIGNAL ;
    ANTENNAGATEAREA 0.159000 ;
    PORT
      LAYER met2 ;
        RECT 208.010 996.000 208.290 1000.000 ;
    END
  END input_data[49]
  PIN input_data[4]
    DIRECTION INPUT ;
    USE SIGNAL ;
    ANTENNAGATEAREA 0.159000 ;
    PORT
      LAYER met2 ;
        RECT 21.710 996.000 21.990 1000.000 ;
    END
  END input_data[4]
  PIN input_data[50]
    DIRECTION INPUT ;
    USE SIGNAL ;
    ANTENNAGATEAREA 0.213000 ;
    PORT
      LAYER met2 ;
        RECT 212.150 996.000 212.430 1000.000 ;
    END
  END input_data[50]
  PIN input_data[51]
    DIRECTION INPUT ;
    USE SIGNAL ;
    ANTENNAGATEAREA 0.213000 ;
    PORT
      LAYER met2 ;
        RECT 216.290 996.000 216.570 1000.000 ;
    END
  END input_data[51]
  PIN input_data[52]
    DIRECTION INPUT ;
    USE SIGNAL ;
    ANTENNAGATEAREA 0.159000 ;
    PORT
      LAYER met2 ;
        RECT 220.430 996.000 220.710 1000.000 ;
    END
  END input_data[52]
  PIN input_data[53]
    DIRECTION INPUT ;
    USE SIGNAL ;
    ANTENNAGATEAREA 0.159000 ;
    PORT
      LAYER met2 ;
        RECT 224.570 996.000 224.850 1000.000 ;
    END
  END input_data[53]
  PIN input_data[54]
    DIRECTION INPUT ;
    USE SIGNAL ;
    ANTENNAGATEAREA 0.159000 ;
    PORT
      LAYER met2 ;
        RECT 228.710 996.000 228.990 1000.000 ;
    END
  END input_data[54]
  PIN input_data[55]
    DIRECTION INPUT ;
    USE SIGNAL ;
    ANTENNAGATEAREA 0.213000 ;
    PORT
      LAYER met2 ;
        RECT 232.850 996.000 233.130 1000.000 ;
    END
  END input_data[55]
  PIN input_data[56]
    DIRECTION INPUT ;
    USE SIGNAL ;
    ANTENNAGATEAREA 0.213000 ;
    PORT
      LAYER met2 ;
        RECT 236.990 996.000 237.270 1000.000 ;
    END
  END input_data[56]
  PIN input_data[57]
    DIRECTION INPUT ;
    USE SIGNAL ;
    ANTENNAGATEAREA 0.159000 ;
    PORT
      LAYER met2 ;
        RECT 241.130 996.000 241.410 1000.000 ;
    END
  END input_data[57]
  PIN input_data[58]
    DIRECTION INPUT ;
    USE SIGNAL ;
    ANTENNAGATEAREA 0.159000 ;
    PORT
      LAYER met2 ;
        RECT 245.270 996.000 245.550 1000.000 ;
    END
  END input_data[58]
  PIN input_data[59]
    DIRECTION INPUT ;
    USE SIGNAL ;
    ANTENNAGATEAREA 0.247500 ;
    PORT
      LAYER met2 ;
        RECT 249.410 996.000 249.690 1000.000 ;
    END
  END input_data[59]
  PIN input_data[5]
    DIRECTION INPUT ;
    USE SIGNAL ;
    ANTENNAGATEAREA 0.159000 ;
    PORT
      LAYER met2 ;
        RECT 25.850 996.000 26.130 1000.000 ;
    END
  END input_data[5]
  PIN input_data[60]
    DIRECTION INPUT ;
    USE SIGNAL ;
    ANTENNAGATEAREA 0.159000 ;
    PORT
      LAYER met2 ;
        RECT 253.550 996.000 253.830 1000.000 ;
    END
  END input_data[60]
  PIN input_data[61]
    DIRECTION INPUT ;
    USE SIGNAL ;
    ANTENNAGATEAREA 0.159000 ;
    PORT
      LAYER met2 ;
        RECT 257.690 996.000 257.970 1000.000 ;
    END
  END input_data[61]
  PIN input_data[62]
    DIRECTION INPUT ;
    USE SIGNAL ;
    ANTENNAGATEAREA 0.213000 ;
    PORT
      LAYER met2 ;
        RECT 261.830 996.000 262.110 1000.000 ;
    END
  END input_data[62]
  PIN input_data[63]
    DIRECTION INPUT ;
    USE SIGNAL ;
    PORT
      LAYER met2 ;
        RECT 265.970 996.000 266.250 1000.000 ;
    END
  END input_data[63]
  PIN input_data[64]
    DIRECTION INPUT ;
    USE SIGNAL ;
    ANTENNAGATEAREA 0.196500 ;
    PORT
      LAYER met2 ;
        RECT 270.110 996.000 270.390 1000.000 ;
    END
  END input_data[64]
  PIN input_data[65]
    DIRECTION INPUT ;
    USE SIGNAL ;
    ANTENNAGATEAREA 0.426000 ;
    PORT
      LAYER met2 ;
        RECT 274.250 996.000 274.530 1000.000 ;
    END
  END input_data[65]
  PIN input_data[66]
    DIRECTION INPUT ;
    USE SIGNAL ;
    ANTENNAGATEAREA 0.196500 ;
    PORT
      LAYER met2 ;
        RECT 278.390 996.000 278.670 1000.000 ;
    END
  END input_data[66]
  PIN input_data[67]
    DIRECTION INPUT ;
    USE SIGNAL ;
    ANTENNAGATEAREA 0.196500 ;
    PORT
      LAYER met2 ;
        RECT 282.530 996.000 282.810 1000.000 ;
    END
  END input_data[67]
  PIN input_data[68]
    DIRECTION INPUT ;
    USE SIGNAL ;
    ANTENNAGATEAREA 0.196500 ;
    PORT
      LAYER met2 ;
        RECT 286.670 996.000 286.950 1000.000 ;
    END
  END input_data[68]
  PIN input_data[69]
    DIRECTION INPUT ;
    USE SIGNAL ;
    ANTENNAGATEAREA 0.196500 ;
    PORT
      LAYER met2 ;
        RECT 290.810 996.000 291.090 1000.000 ;
    END
  END input_data[69]
  PIN input_data[6]
    DIRECTION INPUT ;
    USE SIGNAL ;
    ANTENNAGATEAREA 0.213000 ;
    PORT
      LAYER met2 ;
        RECT 29.990 996.000 30.270 1000.000 ;
    END
  END input_data[6]
  PIN input_data[70]
    DIRECTION INPUT ;
    USE SIGNAL ;
    ANTENNAGATEAREA 0.196500 ;
    PORT
      LAYER met2 ;
        RECT 294.950 996.000 295.230 1000.000 ;
    END
  END input_data[70]
  PIN input_data[71]
    DIRECTION INPUT ;
    USE SIGNAL ;
    ANTENNAGATEAREA 0.213000 ;
    PORT
      LAYER met2 ;
        RECT 299.090 996.000 299.370 1000.000 ;
    END
  END input_data[71]
  PIN input_data[72]
    DIRECTION INPUT ;
    USE SIGNAL ;
    ANTENNAGATEAREA 0.196500 ;
    PORT
      LAYER met2 ;
        RECT 303.230 996.000 303.510 1000.000 ;
    END
  END input_data[72]
  PIN input_data[73]
    DIRECTION INPUT ;
    USE SIGNAL ;
    ANTENNAGATEAREA 0.213000 ;
    PORT
      LAYER met2 ;
        RECT 307.370 996.000 307.650 1000.000 ;
    END
  END input_data[73]
  PIN input_data[74]
    DIRECTION INPUT ;
    USE SIGNAL ;
    ANTENNAGATEAREA 0.213000 ;
    PORT
      LAYER met2 ;
        RECT 311.510 996.000 311.790 1000.000 ;
    END
  END input_data[74]
  PIN input_data[75]
    DIRECTION INPUT ;
    USE SIGNAL ;
    ANTENNAGATEAREA 0.196500 ;
    PORT
      LAYER met2 ;
        RECT 315.650 996.000 315.930 1000.000 ;
    END
  END input_data[75]
  PIN input_data[76]
    DIRECTION INPUT ;
    USE SIGNAL ;
    ANTENNAGATEAREA 0.196500 ;
    PORT
      LAYER met2 ;
        RECT 319.790 996.000 320.070 1000.000 ;
    END
  END input_data[76]
  PIN input_data[77]
    DIRECTION INPUT ;
    USE SIGNAL ;
    ANTENNAGATEAREA 0.213000 ;
    PORT
      LAYER met2 ;
        RECT 323.930 996.000 324.210 1000.000 ;
    END
  END input_data[77]
  PIN input_data[78]
    DIRECTION INPUT ;
    USE SIGNAL ;
    ANTENNAGATEAREA 0.196500 ;
    PORT
      LAYER met2 ;
        RECT 328.070 996.000 328.350 1000.000 ;
    END
  END input_data[78]
  PIN input_data[79]
    DIRECTION INPUT ;
    USE SIGNAL ;
    PORT
      LAYER met2 ;
        RECT 332.210 996.000 332.490 1000.000 ;
    END
  END input_data[79]
  PIN input_data[7]
    DIRECTION INPUT ;
    USE SIGNAL ;
    ANTENNAGATEAREA 0.159000 ;
    PORT
      LAYER met2 ;
        RECT 34.130 996.000 34.410 1000.000 ;
    END
  END input_data[7]
  PIN input_data[80]
    DIRECTION INPUT ;
    USE SIGNAL ;
    ANTENNAGATEAREA 0.213000 ;
    PORT
      LAYER met2 ;
        RECT 336.350 996.000 336.630 1000.000 ;
    END
  END input_data[80]
  PIN input_data[81]
    DIRECTION INPUT ;
    USE SIGNAL ;
    ANTENNAGATEAREA 0.213000 ;
    PORT
      LAYER met2 ;
        RECT 340.490 996.000 340.770 1000.000 ;
    END
  END input_data[81]
  PIN input_data[82]
    DIRECTION INPUT ;
    USE SIGNAL ;
    ANTENNAGATEAREA 0.213000 ;
    PORT
      LAYER met2 ;
        RECT 344.630 996.000 344.910 1000.000 ;
    END
  END input_data[82]
  PIN input_data[83]
    DIRECTION INPUT ;
    USE SIGNAL ;
    ANTENNAGATEAREA 0.247500 ;
    PORT
      LAYER met2 ;
        RECT 348.770 996.000 349.050 1000.000 ;
    END
  END input_data[83]
  PIN input_data[84]
    DIRECTION INPUT ;
    USE SIGNAL ;
    ANTENNAGATEAREA 0.213000 ;
    PORT
      LAYER met2 ;
        RECT 352.910 996.000 353.190 1000.000 ;
    END
  END input_data[84]
  PIN input_data[85]
    DIRECTION INPUT ;
    USE SIGNAL ;
    ANTENNAGATEAREA 0.247500 ;
    PORT
      LAYER met2 ;
        RECT 357.050 996.000 357.330 1000.000 ;
    END
  END input_data[85]
  PIN input_data[86]
    DIRECTION INPUT ;
    USE SIGNAL ;
    ANTENNAGATEAREA 0.426000 ;
    PORT
      LAYER met2 ;
        RECT 361.190 996.000 361.470 1000.000 ;
    END
  END input_data[86]
  PIN input_data[87]
    DIRECTION INPUT ;
    USE SIGNAL ;
    ANTENNAGATEAREA 0.426000 ;
    PORT
      LAYER met2 ;
        RECT 365.330 996.000 365.610 1000.000 ;
    END
  END input_data[87]
  PIN input_data[88]
    DIRECTION INPUT ;
    USE SIGNAL ;
    ANTENNAGATEAREA 0.426000 ;
    PORT
      LAYER met2 ;
        RECT 369.470 996.000 369.750 1000.000 ;
    END
  END input_data[88]
  PIN input_data[89]
    DIRECTION INPUT ;
    USE SIGNAL ;
    ANTENNAGATEAREA 0.247500 ;
    PORT
      LAYER met2 ;
        RECT 373.610 996.000 373.890 1000.000 ;
    END
  END input_data[89]
  PIN input_data[8]
    DIRECTION INPUT ;
    USE SIGNAL ;
    ANTENNAGATEAREA 0.213000 ;
    PORT
      LAYER met2 ;
        RECT 38.270 996.000 38.550 1000.000 ;
    END
  END input_data[8]
  PIN input_data[90]
    DIRECTION INPUT ;
    USE SIGNAL ;
    ANTENNAGATEAREA 0.213000 ;
    PORT
      LAYER met2 ;
        RECT 377.750 996.000 378.030 1000.000 ;
    END
  END input_data[90]
  PIN input_data[91]
    DIRECTION INPUT ;
    USE SIGNAL ;
    ANTENNAGATEAREA 0.426000 ;
    PORT
      LAYER met2 ;
        RECT 381.890 996.000 382.170 1000.000 ;
    END
  END input_data[91]
  PIN input_data[92]
    DIRECTION INPUT ;
    USE SIGNAL ;
    ANTENNAGATEAREA 0.426000 ;
    PORT
      LAYER met2 ;
        RECT 386.030 996.000 386.310 1000.000 ;
    END
  END input_data[92]
  PIN input_data[93]
    DIRECTION INPUT ;
    USE SIGNAL ;
    ANTENNAGATEAREA 0.495000 ;
    PORT
      LAYER met2 ;
        RECT 390.170 996.000 390.450 1000.000 ;
    END
  END input_data[93]
  PIN input_data[94]
    DIRECTION INPUT ;
    USE SIGNAL ;
    ANTENNAGATEAREA 0.247500 ;
    PORT
      LAYER met2 ;
        RECT 394.310 996.000 394.590 1000.000 ;
    END
  END input_data[94]
  PIN input_data[95]
    DIRECTION INPUT ;
    USE SIGNAL ;
    ANTENNAGATEAREA 0.213000 ;
    PORT
      LAYER met2 ;
        RECT 398.450 996.000 398.730 1000.000 ;
    END
  END input_data[95]
  PIN input_data[96]
    DIRECTION INPUT ;
    USE SIGNAL ;
    ANTENNAGATEAREA 0.213000 ;
    PORT
      LAYER met2 ;
        RECT 402.590 996.000 402.870 1000.000 ;
    END
  END input_data[96]
  PIN input_data[97]
    DIRECTION INPUT ;
    USE SIGNAL ;
    ANTENNAGATEAREA 0.196500 ;
    PORT
      LAYER met2 ;
        RECT 406.730 996.000 407.010 1000.000 ;
    END
  END input_data[97]
  PIN input_data[98]
    DIRECTION INPUT ;
    USE SIGNAL ;
    ANTENNAGATEAREA 0.196500 ;
    PORT
      LAYER met2 ;
        RECT 410.870 996.000 411.150 1000.000 ;
    END
  END input_data[98]
  PIN input_data[99]
    DIRECTION INPUT ;
    USE SIGNAL ;
    ANTENNAGATEAREA 0.196500 ;
    PORT
      LAYER met2 ;
        RECT 415.010 996.000 415.290 1000.000 ;
    END
  END input_data[99]
  PIN input_data[9]
    DIRECTION INPUT ;
    USE SIGNAL ;
    ANTENNAGATEAREA 0.426000 ;
    PORT
      LAYER met2 ;
        RECT 42.410 996.000 42.690 1000.000 ;
    END
  END input_data[9]
  PIN output_high[0]
    DIRECTION OUTPUT ;
    USE SIGNAL ;
    ANTENNADIFFAREA 0.445500 ;
    PORT
      LAYER met3 ;
        RECT 0.000 39.480 4.000 40.080 ;
    END
  END output_high[0]
  PIN output_high[10]
    DIRECTION OUTPUT ;
    USE SIGNAL ;
    ANTENNADIFFAREA 0.445500 ;
    PORT
      LAYER met3 ;
        RECT 0.000 651.480 4.000 652.080 ;
    END
  END output_high[10]
  PIN output_high[11]
    DIRECTION OUTPUT ;
    USE SIGNAL ;
    ANTENNADIFFAREA 0.445500 ;
    PORT
      LAYER met3 ;
        RECT 0.000 712.680 4.000 713.280 ;
    END
  END output_high[11]
  PIN output_high[12]
    DIRECTION OUTPUT ;
    USE SIGNAL ;
    ANTENNADIFFAREA 0.445500 ;
    PORT
      LAYER met3 ;
        RECT 0.000 773.880 4.000 774.480 ;
    END
  END output_high[12]
  PIN output_high[13]
    DIRECTION OUTPUT ;
    USE SIGNAL ;
    ANTENNADIFFAREA 0.445500 ;
    PORT
      LAYER met3 ;
        RECT 0.000 835.080 4.000 835.680 ;
    END
  END output_high[13]
  PIN output_high[14]
    DIRECTION OUTPUT ;
    USE SIGNAL ;
    ANTENNADIFFAREA 0.445500 ;
    PORT
      LAYER met3 ;
        RECT 0.000 896.280 4.000 896.880 ;
    END
  END output_high[14]
  PIN output_high[15]
    DIRECTION OUTPUT ;
    USE SIGNAL ;
    ANTENNADIFFAREA 0.445500 ;
    PORT
      LAYER met3 ;
        RECT 0.000 957.480 4.000 958.080 ;
    END
  END output_high[15]
  PIN output_high[1]
    DIRECTION OUTPUT ;
    USE SIGNAL ;
    ANTENNADIFFAREA 0.445500 ;
    PORT
      LAYER met3 ;
        RECT 0.000 100.680 4.000 101.280 ;
    END
  END output_high[1]
  PIN output_high[2]
    DIRECTION OUTPUT ;
    USE SIGNAL ;
    ANTENNADIFFAREA 0.445500 ;
    PORT
      LAYER met3 ;
        RECT 0.000 161.880 4.000 162.480 ;
    END
  END output_high[2]
  PIN output_high[3]
    DIRECTION OUTPUT ;
    USE SIGNAL ;
    ANTENNADIFFAREA 0.445500 ;
    PORT
      LAYER met3 ;
        RECT 0.000 223.080 4.000 223.680 ;
    END
  END output_high[3]
  PIN output_high[4]
    DIRECTION OUTPUT ;
    USE SIGNAL ;
    ANTENNADIFFAREA 0.445500 ;
    PORT
      LAYER met3 ;
        RECT 0.000 284.280 4.000 284.880 ;
    END
  END output_high[4]
  PIN output_high[5]
    DIRECTION OUTPUT ;
    USE SIGNAL ;
    ANTENNADIFFAREA 0.445500 ;
    PORT
      LAYER met3 ;
        RECT 0.000 345.480 4.000 346.080 ;
    END
  END output_high[5]
  PIN output_high[6]
    DIRECTION OUTPUT ;
    USE SIGNAL ;
    ANTENNADIFFAREA 0.445500 ;
    PORT
      LAYER met3 ;
        RECT 0.000 406.680 4.000 407.280 ;
    END
  END output_high[6]
  PIN output_high[7]
    DIRECTION OUTPUT ;
    USE SIGNAL ;
    ANTENNADIFFAREA 0.445500 ;
    PORT
      LAYER met3 ;
        RECT 0.000 467.880 4.000 468.480 ;
    END
  END output_high[7]
  PIN output_high[8]
    DIRECTION OUTPUT ;
    USE SIGNAL ;
    ANTENNADIFFAREA 0.445500 ;
    PORT
      LAYER met3 ;
        RECT 0.000 529.080 4.000 529.680 ;
    END
  END output_high[8]
  PIN output_high[9]
    DIRECTION OUTPUT ;
    USE SIGNAL ;
    ANTENNADIFFAREA 0.445500 ;
    PORT
      LAYER met3 ;
        RECT 0.000 590.280 4.000 590.880 ;
    END
  END output_high[9]
  PIN tap[0]
    DIRECTION INPUT ;
    USE SIGNAL ;
    ANTENNAGATEAREA 0.247500 ;
    PORT
      LAYER met2 ;
        RECT 125.210 0.000 125.490 4.000 ;
    END
  END tap[0]
  PIN tap[1]
    DIRECTION INPUT ;
    USE SIGNAL ;
    ANTENNAGATEAREA 0.247500 ;
    PORT
      LAYER met2 ;
        RECT 374.990 0.000 375.270 4.000 ;
    END
  END tap[1]
  PIN tap[2]
    DIRECTION INPUT ;
    USE SIGNAL ;
    ANTENNAGATEAREA 0.742500 ;
    PORT
      LAYER met2 ;
        RECT 624.770 0.000 625.050 4.000 ;
    END
  END tap[2]
  PIN tap[3]
    DIRECTION INPUT ;
    USE SIGNAL ;
    ANTENNAGATEAREA 0.852000 ;
    PORT
      LAYER met2 ;
        RECT 874.550 0.000 874.830 4.000 ;
    END
  END tap[3]
  OBS
      LAYER li1 ;
        RECT 5.520 10.795 994.060 987.445 ;
      LAYER met1 ;
        RECT 3.750 10.640 994.060 987.600 ;
      LAYER met2 ;
        RECT 3.770 995.720 4.870 996.610 ;
        RECT 5.710 995.720 9.010 996.610 ;
        RECT 9.850 995.720 13.150 996.610 ;
        RECT 13.990 995.720 17.290 996.610 ;
        RECT 18.130 995.720 21.430 996.610 ;
        RECT 22.270 995.720 25.570 996.610 ;
        RECT 26.410 995.720 29.710 996.610 ;
        RECT 30.550 995.720 33.850 996.610 ;
        RECT 34.690 995.720 37.990 996.610 ;
        RECT 38.830 995.720 42.130 996.610 ;
        RECT 42.970 995.720 46.270 996.610 ;
        RECT 47.110 995.720 50.410 996.610 ;
        RECT 51.250 995.720 54.550 996.610 ;
        RECT 55.390 995.720 58.690 996.610 ;
        RECT 59.530 995.720 62.830 996.610 ;
        RECT 63.670 995.720 66.970 996.610 ;
        RECT 67.810 995.720 71.110 996.610 ;
        RECT 71.950 995.720 75.250 996.610 ;
        RECT 76.090 995.720 79.390 996.610 ;
        RECT 80.230 995.720 83.530 996.610 ;
        RECT 84.370 995.720 87.670 996.610 ;
        RECT 88.510 995.720 91.810 996.610 ;
        RECT 92.650 995.720 95.950 996.610 ;
        RECT 96.790 995.720 100.090 996.610 ;
        RECT 100.930 995.720 104.230 996.610 ;
        RECT 105.070 995.720 108.370 996.610 ;
        RECT 109.210 995.720 112.510 996.610 ;
        RECT 113.350 995.720 116.650 996.610 ;
        RECT 117.490 995.720 120.790 996.610 ;
        RECT 121.630 995.720 124.930 996.610 ;
        RECT 125.770 995.720 129.070 996.610 ;
        RECT 129.910 995.720 133.210 996.610 ;
        RECT 134.050 995.720 137.350 996.610 ;
        RECT 138.190 995.720 141.490 996.610 ;
        RECT 142.330 995.720 145.630 996.610 ;
        RECT 146.470 995.720 149.770 996.610 ;
        RECT 150.610 995.720 153.910 996.610 ;
        RECT 154.750 995.720 158.050 996.610 ;
        RECT 158.890 995.720 162.190 996.610 ;
        RECT 163.030 995.720 166.330 996.610 ;
        RECT 167.170 995.720 170.470 996.610 ;
        RECT 171.310 995.720 174.610 996.610 ;
        RECT 175.450 995.720 178.750 996.610 ;
        RECT 179.590 995.720 182.890 996.610 ;
        RECT 183.730 995.720 187.030 996.610 ;
        RECT 187.870 995.720 191.170 996.610 ;
        RECT 192.010 995.720 195.310 996.610 ;
        RECT 196.150 995.720 199.450 996.610 ;
        RECT 200.290 995.720 203.590 996.610 ;
        RECT 204.430 995.720 207.730 996.610 ;
        RECT 208.570 995.720 211.870 996.610 ;
        RECT 212.710 995.720 216.010 996.610 ;
        RECT 216.850 995.720 220.150 996.610 ;
        RECT 220.990 995.720 224.290 996.610 ;
        RECT 225.130 995.720 228.430 996.610 ;
        RECT 229.270 995.720 232.570 996.610 ;
        RECT 233.410 995.720 236.710 996.610 ;
        RECT 237.550 995.720 240.850 996.610 ;
        RECT 241.690 995.720 244.990 996.610 ;
        RECT 245.830 995.720 249.130 996.610 ;
        RECT 249.970 995.720 253.270 996.610 ;
        RECT 254.110 995.720 257.410 996.610 ;
        RECT 258.250 995.720 261.550 996.610 ;
        RECT 262.390 995.720 265.690 996.610 ;
        RECT 266.530 995.720 269.830 996.610 ;
        RECT 270.670 995.720 273.970 996.610 ;
        RECT 274.810 995.720 278.110 996.610 ;
        RECT 278.950 995.720 282.250 996.610 ;
        RECT 283.090 995.720 286.390 996.610 ;
        RECT 287.230 995.720 290.530 996.610 ;
        RECT 291.370 995.720 294.670 996.610 ;
        RECT 295.510 995.720 298.810 996.610 ;
        RECT 299.650 995.720 302.950 996.610 ;
        RECT 303.790 995.720 307.090 996.610 ;
        RECT 307.930 995.720 311.230 996.610 ;
        RECT 312.070 995.720 315.370 996.610 ;
        RECT 316.210 995.720 319.510 996.610 ;
        RECT 320.350 995.720 323.650 996.610 ;
        RECT 324.490 995.720 327.790 996.610 ;
        RECT 328.630 995.720 331.930 996.610 ;
        RECT 332.770 995.720 336.070 996.610 ;
        RECT 336.910 995.720 340.210 996.610 ;
        RECT 341.050 995.720 344.350 996.610 ;
        RECT 345.190 995.720 348.490 996.610 ;
        RECT 349.330 995.720 352.630 996.610 ;
        RECT 353.470 995.720 356.770 996.610 ;
        RECT 357.610 995.720 360.910 996.610 ;
        RECT 361.750 995.720 365.050 996.610 ;
        RECT 365.890 995.720 369.190 996.610 ;
        RECT 370.030 995.720 373.330 996.610 ;
        RECT 374.170 995.720 377.470 996.610 ;
        RECT 378.310 995.720 381.610 996.610 ;
        RECT 382.450 995.720 385.750 996.610 ;
        RECT 386.590 995.720 389.890 996.610 ;
        RECT 390.730 995.720 394.030 996.610 ;
        RECT 394.870 995.720 398.170 996.610 ;
        RECT 399.010 995.720 402.310 996.610 ;
        RECT 403.150 995.720 406.450 996.610 ;
        RECT 407.290 995.720 410.590 996.610 ;
        RECT 411.430 995.720 414.730 996.610 ;
        RECT 415.570 995.720 418.870 996.610 ;
        RECT 419.710 995.720 423.010 996.610 ;
        RECT 423.850 995.720 427.150 996.610 ;
        RECT 427.990 995.720 431.290 996.610 ;
        RECT 432.130 995.720 435.430 996.610 ;
        RECT 436.270 995.720 439.570 996.610 ;
        RECT 440.410 995.720 443.710 996.610 ;
        RECT 444.550 995.720 447.850 996.610 ;
        RECT 448.690 995.720 451.990 996.610 ;
        RECT 452.830 995.720 456.130 996.610 ;
        RECT 456.970 995.720 460.270 996.610 ;
        RECT 461.110 995.720 464.410 996.610 ;
        RECT 465.250 995.720 468.550 996.610 ;
        RECT 469.390 995.720 472.690 996.610 ;
        RECT 473.530 995.720 476.830 996.610 ;
        RECT 477.670 995.720 480.970 996.610 ;
        RECT 481.810 995.720 485.110 996.610 ;
        RECT 485.950 995.720 489.250 996.610 ;
        RECT 490.090 995.720 493.390 996.610 ;
        RECT 494.230 995.720 497.530 996.610 ;
        RECT 498.370 995.720 501.670 996.610 ;
        RECT 502.510 995.720 505.810 996.610 ;
        RECT 506.650 995.720 509.950 996.610 ;
        RECT 510.790 995.720 514.090 996.610 ;
        RECT 514.930 995.720 518.230 996.610 ;
        RECT 519.070 995.720 522.370 996.610 ;
        RECT 523.210 995.720 526.510 996.610 ;
        RECT 527.350 995.720 530.650 996.610 ;
        RECT 531.490 995.720 534.790 996.610 ;
        RECT 535.630 995.720 538.930 996.610 ;
        RECT 539.770 995.720 543.070 996.610 ;
        RECT 543.910 995.720 547.210 996.610 ;
        RECT 548.050 995.720 551.350 996.610 ;
        RECT 552.190 995.720 555.490 996.610 ;
        RECT 556.330 995.720 559.630 996.610 ;
        RECT 560.470 995.720 563.770 996.610 ;
        RECT 564.610 995.720 567.910 996.610 ;
        RECT 568.750 995.720 572.050 996.610 ;
        RECT 572.890 995.720 576.190 996.610 ;
        RECT 577.030 995.720 580.330 996.610 ;
        RECT 581.170 995.720 584.470 996.610 ;
        RECT 585.310 995.720 588.610 996.610 ;
        RECT 589.450 995.720 592.750 996.610 ;
        RECT 593.590 995.720 596.890 996.610 ;
        RECT 597.730 995.720 601.030 996.610 ;
        RECT 601.870 995.720 605.170 996.610 ;
        RECT 606.010 995.720 609.310 996.610 ;
        RECT 610.150 995.720 613.450 996.610 ;
        RECT 614.290 995.720 617.590 996.610 ;
        RECT 618.430 995.720 621.730 996.610 ;
        RECT 622.570 995.720 625.870 996.610 ;
        RECT 626.710 995.720 630.010 996.610 ;
        RECT 630.850 995.720 634.150 996.610 ;
        RECT 634.990 995.720 638.290 996.610 ;
        RECT 639.130 995.720 642.430 996.610 ;
        RECT 643.270 995.720 646.570 996.610 ;
        RECT 647.410 995.720 650.710 996.610 ;
        RECT 651.550 995.720 654.850 996.610 ;
        RECT 655.690 995.720 658.990 996.610 ;
        RECT 659.830 995.720 663.130 996.610 ;
        RECT 663.970 995.720 667.270 996.610 ;
        RECT 668.110 995.720 671.410 996.610 ;
        RECT 672.250 995.720 675.550 996.610 ;
        RECT 676.390 995.720 679.690 996.610 ;
        RECT 680.530 995.720 683.830 996.610 ;
        RECT 684.670 995.720 687.970 996.610 ;
        RECT 688.810 995.720 692.110 996.610 ;
        RECT 692.950 995.720 696.250 996.610 ;
        RECT 697.090 995.720 700.390 996.610 ;
        RECT 701.230 995.720 704.530 996.610 ;
        RECT 705.370 995.720 708.670 996.610 ;
        RECT 709.510 995.720 712.810 996.610 ;
        RECT 713.650 995.720 716.950 996.610 ;
        RECT 717.790 995.720 721.090 996.610 ;
        RECT 721.930 995.720 725.230 996.610 ;
        RECT 726.070 995.720 729.370 996.610 ;
        RECT 730.210 995.720 733.510 996.610 ;
        RECT 734.350 995.720 737.650 996.610 ;
        RECT 738.490 995.720 741.790 996.610 ;
        RECT 742.630 995.720 745.930 996.610 ;
        RECT 746.770 995.720 750.070 996.610 ;
        RECT 750.910 995.720 754.210 996.610 ;
        RECT 755.050 995.720 758.350 996.610 ;
        RECT 759.190 995.720 762.490 996.610 ;
        RECT 763.330 995.720 766.630 996.610 ;
        RECT 767.470 995.720 770.770 996.610 ;
        RECT 771.610 995.720 774.910 996.610 ;
        RECT 775.750 995.720 779.050 996.610 ;
        RECT 779.890 995.720 783.190 996.610 ;
        RECT 784.030 995.720 787.330 996.610 ;
        RECT 788.170 995.720 791.470 996.610 ;
        RECT 792.310 995.720 795.610 996.610 ;
        RECT 796.450 995.720 799.750 996.610 ;
        RECT 800.590 995.720 803.890 996.610 ;
        RECT 804.730 995.720 808.030 996.610 ;
        RECT 808.870 995.720 812.170 996.610 ;
        RECT 813.010 995.720 816.310 996.610 ;
        RECT 817.150 995.720 820.450 996.610 ;
        RECT 821.290 995.720 824.590 996.610 ;
        RECT 825.430 995.720 828.730 996.610 ;
        RECT 829.570 995.720 832.870 996.610 ;
        RECT 833.710 995.720 837.010 996.610 ;
        RECT 837.850 995.720 841.150 996.610 ;
        RECT 841.990 995.720 845.290 996.610 ;
        RECT 846.130 995.720 849.430 996.610 ;
        RECT 850.270 995.720 853.570 996.610 ;
        RECT 854.410 995.720 857.710 996.610 ;
        RECT 858.550 995.720 861.850 996.610 ;
        RECT 862.690 995.720 865.990 996.610 ;
        RECT 866.830 995.720 870.130 996.610 ;
        RECT 870.970 995.720 874.270 996.610 ;
        RECT 875.110 995.720 878.410 996.610 ;
        RECT 879.250 995.720 882.550 996.610 ;
        RECT 883.390 995.720 886.690 996.610 ;
        RECT 887.530 995.720 890.830 996.610 ;
        RECT 891.670 995.720 894.970 996.610 ;
        RECT 895.810 995.720 899.110 996.610 ;
        RECT 899.950 995.720 903.250 996.610 ;
        RECT 904.090 995.720 907.390 996.610 ;
        RECT 908.230 995.720 911.530 996.610 ;
        RECT 912.370 995.720 915.670 996.610 ;
        RECT 916.510 995.720 919.810 996.610 ;
        RECT 920.650 995.720 923.950 996.610 ;
        RECT 924.790 995.720 928.090 996.610 ;
        RECT 928.930 995.720 932.230 996.610 ;
        RECT 933.070 995.720 936.370 996.610 ;
        RECT 937.210 995.720 940.510 996.610 ;
        RECT 941.350 995.720 944.650 996.610 ;
        RECT 945.490 995.720 948.790 996.610 ;
        RECT 949.630 995.720 952.930 996.610 ;
        RECT 953.770 995.720 957.070 996.610 ;
        RECT 957.910 995.720 961.210 996.610 ;
        RECT 962.050 995.720 965.350 996.610 ;
        RECT 966.190 995.720 969.490 996.610 ;
        RECT 970.330 995.720 973.630 996.610 ;
        RECT 974.470 995.720 977.770 996.610 ;
        RECT 978.610 995.720 981.910 996.610 ;
        RECT 982.750 995.720 986.050 996.610 ;
        RECT 986.890 995.720 987.060 996.610 ;
        RECT 3.770 4.280 987.060 995.720 ;
        RECT 3.770 4.000 124.930 4.280 ;
        RECT 125.770 4.000 374.710 4.280 ;
        RECT 375.550 4.000 624.490 4.280 ;
        RECT 625.330 4.000 874.270 4.280 ;
        RECT 875.110 4.000 987.060 4.280 ;
      LAYER met3 ;
        RECT 3.745 958.480 996.000 987.525 ;
        RECT 4.400 957.080 996.000 958.480 ;
        RECT 3.745 897.280 996.000 957.080 ;
        RECT 4.400 895.880 996.000 897.280 ;
        RECT 3.745 836.080 996.000 895.880 ;
        RECT 4.400 834.680 996.000 836.080 ;
        RECT 3.745 774.880 996.000 834.680 ;
        RECT 4.400 773.480 996.000 774.880 ;
        RECT 3.745 713.680 996.000 773.480 ;
        RECT 4.400 712.280 996.000 713.680 ;
        RECT 3.745 652.480 996.000 712.280 ;
        RECT 4.400 651.080 996.000 652.480 ;
        RECT 3.745 591.280 996.000 651.080 ;
        RECT 4.400 589.880 996.000 591.280 ;
        RECT 3.745 530.080 996.000 589.880 ;
        RECT 4.400 528.680 996.000 530.080 ;
        RECT 3.745 500.160 996.000 528.680 ;
        RECT 3.745 498.760 995.600 500.160 ;
        RECT 3.745 468.880 996.000 498.760 ;
        RECT 4.400 467.480 996.000 468.880 ;
        RECT 3.745 407.680 996.000 467.480 ;
        RECT 4.400 406.280 996.000 407.680 ;
        RECT 3.745 346.480 996.000 406.280 ;
        RECT 4.400 345.080 996.000 346.480 ;
        RECT 3.745 285.280 996.000 345.080 ;
        RECT 4.400 283.880 996.000 285.280 ;
        RECT 3.745 224.080 996.000 283.880 ;
        RECT 4.400 222.680 996.000 224.080 ;
        RECT 3.745 162.880 996.000 222.680 ;
        RECT 4.400 161.480 996.000 162.880 ;
        RECT 3.745 101.680 996.000 161.480 ;
        RECT 4.400 100.280 996.000 101.680 ;
        RECT 3.745 40.480 996.000 100.280 ;
        RECT 4.400 39.080 996.000 40.480 ;
        RECT 3.745 10.715 996.000 39.080 ;
      LAYER met4 ;
        RECT 3.975 445.575 20.640 983.785 ;
        RECT 23.040 445.575 23.940 983.785 ;
        RECT 26.340 445.575 174.240 983.785 ;
        RECT 176.640 445.575 177.540 983.785 ;
        RECT 179.940 445.575 327.840 983.785 ;
        RECT 330.240 445.575 331.140 983.785 ;
        RECT 333.540 445.575 481.440 983.785 ;
        RECT 483.840 445.575 484.740 983.785 ;
        RECT 487.140 445.575 635.040 983.785 ;
        RECT 637.440 445.575 638.340 983.785 ;
        RECT 640.740 445.575 788.145 983.785 ;
      LAYER met5 ;
        RECT 348.340 595.900 697.700 604.300 ;
  END
END highpass
END LIBRARY

